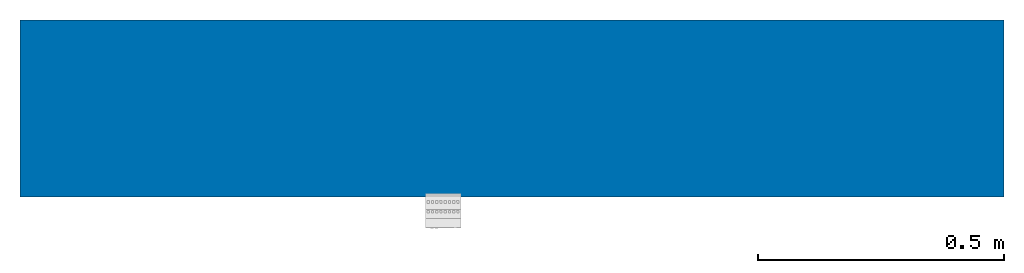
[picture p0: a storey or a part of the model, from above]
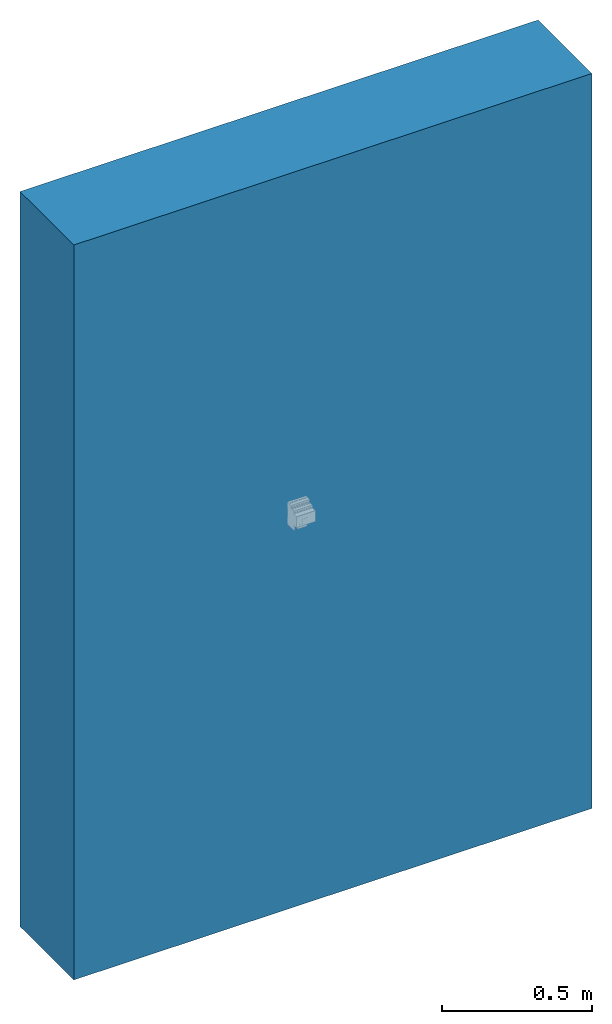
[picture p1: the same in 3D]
Properties of the parts of a building model (IFC2X3)

# File
Description: ViewDefinition [CoordinationView_V2.0]
File name: Projektnummer
Time: 2019-08-29T13:22:09
Written by: The EXPRESS Data Manager Version 5.02.0100.07 : 28 Aug 2013
Made in: 20160225_1515(x64) - Exporter 17.0.416.0 - Alternate UI 17.12.14.0
Comment: STEP Physical File produced by: The EXPRESS Data Manager Version 5.02.0100.07 : 28 Aug 2013 * Module: EDMstepFileFactory/EDMstandAlone * Creation date: Thu Aug 29 13:22:09 2019 * Host: B-BIM-NB-4736 * Database: C:\Users\Enkler\AppData\Local\Temp\{0822E0B0-039E-44F1-9CD0-8C1D5D97FADD}\ifc * Database version: 5507 * Database creation date: Thu Aug 29 13:22:08 2019 * Schema: IFC2X3 * Model: DataRepository.ifc * Model creation date: Thu Aug 29 13:22:08 2019 * Header model: DataRepository.ifc_HeaderModel * Header model creation date: Thu Aug 29 13:22:08 2019 * EDMuser: sdai-user * EDMgroup: sdai-group * License ID and type: 5605 : Permanent license. Expiry date: * EDMstepFileFactory options: 020000

# IfcProject, Projektnummer
LongName: Projektname; Phase: Projektstatus

# IfcSite, Default
RefLatitude: 52, 30, 59, 765625; RefLongitude: 13, 23, 59, 998626; RefElevation: 0 m
Sonstige - Kategorie: Projektinformationen; Kundenname: Bauherr; Projektadresse: Projektadresse; Projektausgabedatum: Projekt Datum; Projektname: Projektname; Projektnummer: Projektnummer; Projektstatus: Projektstatus; Verfasser eMail: E-Mail; Verfasser Firma 1: Firma 1; Verfasser Firma 2: Firma 2; Verfasser PLZ Ort: PLZ Ort; Verfasser Strasse: Strasse; Verfasser Telefax: Telefax; Verfasser Telefon: Telefon

# IfcBuilding
Pset_BuildingCommon - NumberOfStoreys: 1
Sonstige - Kategorie: Projektinformationen; Kundenname: Bauherr; Projektadresse: Projektadresse; Projektausgabedatum: Projekt Datum; Projektname: Projektname; Projektnummer: Projektnummer; Projektstatus: Projektstatus; Verfasser eMail: E-Mail; Verfasser Firma 1: Firma 1; Verfasser Firma 2: Firma 2; Verfasser PLZ Ort: PLZ Ort; Verfasser Strasse: Strasse; Verfasser Telefax: Telefax; Verfasser Telefon: Telefon

# IfcBuildingStorey, Ebene 0
LongName: Ebene 0; Elevation: 0 m
Sonstige - Kategorie: Ebenen; Familienname: Ebene; Familie: Ebene: Ebene; Familie und Typ: Ebene: Ebene; Typ: Ebene: Ebene; Typ-ID: Ebene: Ebene
ID-Daten - Typname: Ebene; Tragwerk: no; Gebäudegeschoss: yes; Name: Ebene 0
Grafiken - Farbe: 16711680; Linienmuster: Verdeckt; Linienstärke: 1; Symbol: Beschriftung Ebene: Beschriftung Ebene; Symbol bei Ende 1 Standard: no; Symbol bei Ende 2 Standard: yes
Abhängigkeiten - Basishöhe: Projekt-Basispunkt; Ansicht: 0 m
Abmessungen - Höhe für Berechnung: 0 m

# IfcBuildingElementProxy: GIRA_212900_ENG, GIRA_212900_ENG:GIRA_212900_ENG:389692
In: Ebene 0
Type - Material: White
Type - Abhängigkeiten - Vorgabe-Ansicht: 1.2192 m
Type - Allgemein - Bus connection included YesNo: no; Bus system KNX radio YesNo: no; Bus system KNX YesNo: yes; Bus system LON YesNo: no; Bus system Powernet YesNo: no; Bus system radio frequent YesNo: no; Degree of protection (IP) Text: IP20; HeinzeBIM: https://www.heinze.de/bim/heat-act-6-g-cont-knx-dra/4d2fb85c400b2ce1da0d762585a9c77f87d992d0; Mounting method Text: DRA (DIN-rail adapter); Other bus systems Text: Other
Type - Daten - Number of outputs: 6; Width in number of modular spacings Number: 4
Type - ID-Daten - Beschreibung: Heat.act.6g cont.DRA KNX,KNX heating actuator, 6-gang with controller,,DRA plus,Features:,- Heating actuator with integrated room temperature controller for switching electrothermic valve drives for heating or cooling ceilings.,Valve outputs:,- Switching operation or PWM operation.,- Servos with the characteristic de-energised open" or "de-energised closed" can be controlled.,- Servos can be activated with rated voltage 24 V or 230 V.,- Building site operation: Outputs can be operated manually without bus voltage with operating voltage only.,- Feedback in manual actuation and in bus operation.,- Blocking of individual outputs manually or with bus.,- Overload protected, short-circuit protected, errors indicated with LED.,- Protection against jammed valves.,- Forced setting.,- Various setpoint values for forced setting or emergency mode in case of bus failure for the summer and winter.,- Cyclical monitoring of the input signals can be parameterised.,- Feedback via bus e.g. for valve voltage failure, overload, and short circuit.,- Switching the heating circuit pump depending on the valve conditions.,- Group feedback of the closed servos.,- Power-saving mode for reducing the energy consumption of the heating actuator. Application for periods (e.g. summer) when heat is not required for heating.,- Activation of servo with "first open function" during start-up.,- Fast commissioning thanks to global setting of the channels.,- Cascading of several heating actuators.,- Resetting error messages via bus.,- Heating requirements control.,- Elapsed operating time meter per channel.,Room Temperature Controller:,- 6 independent controllers.,- Control via individual communication objects for inputs and outputs.,- Optional internal group communication for individual assignment of the controller outputs to the output channels of the actuator.,- Operating modes: Comfort, standby, night, and frost heat protection.,- Each operating mode can be assigned its own setpoint temperature values.,- Configuration of the temperature setpoints either relative (derived from basic setpoint) or absolute (independent setpoint temperatures for each operating mode).,- Comfort extension using the presence button, duration parameterisable.,- Operating mode changeover using 1-byte objects in accordance with the KNX specification or by up to 4 individual 1-bit objects.,- Configurable status feedback.,- Frost heat protection changeover via window status or via frost protection automatic function.,- "Heating", "Cooling" and "Heating and Cooling" operating modes respectively with or without additional stage. The temperature setpoints for the additional stage are derived by a parameterisable stage interval from the basic stage values.,- Various control types can be configured according to the heating or cooling level: PI control (constant or switching PWM) or 2-point control (switching).,- Control parameters for PI controller (if desired: proportional area, readjustment time) and 2-point controller (hysteresis) can be set.,- Automatic and object-oriented switching between "Heating" and "Cooling".,- Room temperature measurement via up to two external KNX temperature sensors. Comparison of the temperature values is possible and the measured value generation of the external sensors can be parameterised. Query time of the externally received temperature values can be set.,- The actual and setpoint temperatures can be output to the bus (incl. cyclical) after a parameterisable deviation.,- Separate or joint corrected variable output in heating or cooling mode. This results in one or two corrected variable objects per stage.,- Normal or inverted corrected variable output.,- Automatic transmission and cycle time for corrected variable output can be parameterised.,- Variable limitation is possible.,- Floor temperature limitation possible in heating mode.,- Setpoint temperature limitation possible in cooling mode.,,Notes :,- Valves with the same operating voltage must be connected at all outputs.,- VDE approval in accordance with EN 60669-1, EN 60669-2-1.,- Installation on DIN top-hat rail."; GTIN: 4010337032915; HAN: 212900; Hersteller: Gira; Typname: GIRA_212900_ENG; URL: https://www.gira.de/
Type - Sonstige - Kategorie: Elektroinstallationen; Familienname: GIRA_212900_ENG
Pset_BuildingElementProxyCommon - Reference: GIRA_212900_ENG
Pset_ManufacturerTypeInformation - Manufacturer: Gira
Abhängigkeiten - Basisbauteil: Basiswand : MW 24.0 WD 12.0; Ebene: Ebene: Ebene 0; Erhebung: 1.6178 m
Abmessungen - Fläche: 0.0179427 m2; Volumen: 0.000458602 m3
ID-Daten - Kennzeichen: 1
Phasen - Phase erstellt: Phase 1
Sonstige - Bauteillistenebene: Ebene: Ebene 0; Familie: GIRA_212900_ENG: GIRA_212900_ENG; Familie und Typ: GIRA_212900_ENG: GIRA_212900_ENG; Typ: GIRA_212900_ENG: GIRA_212900_ENG; Typ-ID: GIRA_212900_ENG: GIRA_212900_ENG

# IfcWallStandardCase: Basiswand:MW 24.0 WD 12.0, Basiswand:MW 24.0 WD 12.0:388641
In: Ebene 0
Type - PredefinedType: STANDARD; Material: Wärmedämmung - hart 0.12 m, Mauerwerk - Ziegel, verputzt 0.24 m
Type - Analytische Eigenschaften - Absorptionsgrad: 0.7; Rauigkeit: 3; Thermischer Widerstand (R): 3.87302; Thermisch wirksame Masse: 316537; Wärmeübergangskoeffizient (U): 0.258197
Type - Grafiken - Farbfüllung für groben Maßstab: 0; Füllmuster für groben Maßstab: Standard - Füllung
Type - ID-Daten - Beschreibung: Mauerwerk 24.0 cm, Wärmedämmung 12.0 cm; Typenkommentare: Mehrschaliges Mauerwerk; Typname: MW 24.0 WD 12.0
Type - Konstruktion - Abschluss an Öffnungen: Keine; Abschluss an Wänden: Keine; Breite: 0.36 m; Funktion: Außen
Type - Materialien und Oberflächen - Tragendes Material: Mauerwerk - Ziegel, verputzt
Type - Sonstige - Kategorie: Wände; Familienname: Basiswand
Abhängigkeiten - Abhängigkeit oben: Ebene: Ebene 1; Abhängigkeit unten: Ebene: Ebene 0; Basislinie: Wandachse; Für Körper: no; Nicht verknüpfte Höhe: 3 m; Oberkante ist fixiert.: no; Raumbegrenzung: yes; Unterkante ist fixiert: no; Verlängerungsabstand oben: 0 m; Verlängerungsabstand unten: 0 m; Versatz oben: 0 m; Versatz unten: 0 m
Abmessungen - Fläche: 6 m2; Länge: 2 m; Volumen: 2.16 m3
Phasen - Phase erstellt: Phase 1
Sonstige - Familie: Basiswand: MW 24.0 WD 12.0; Familie und Typ: Basiswand: MW 24.0 WD 12.0; Typ: Basiswand: MW 24.0 WD 12.0; Typ-ID: Basiswand: MW 24.0 WD 12.0
Tragwerk - Berechnungsmodell aktivieren: no; Tragwerk: no; Tragwerksverwendung: Nichttragend
Pset_WallCommon - Reference: MW 24.0 WD 12.0; LoadBearing: no; ExtendToStructure: no; IsExternal: yes; ThermalTransmittance: 0.258197 kg/K/s3
